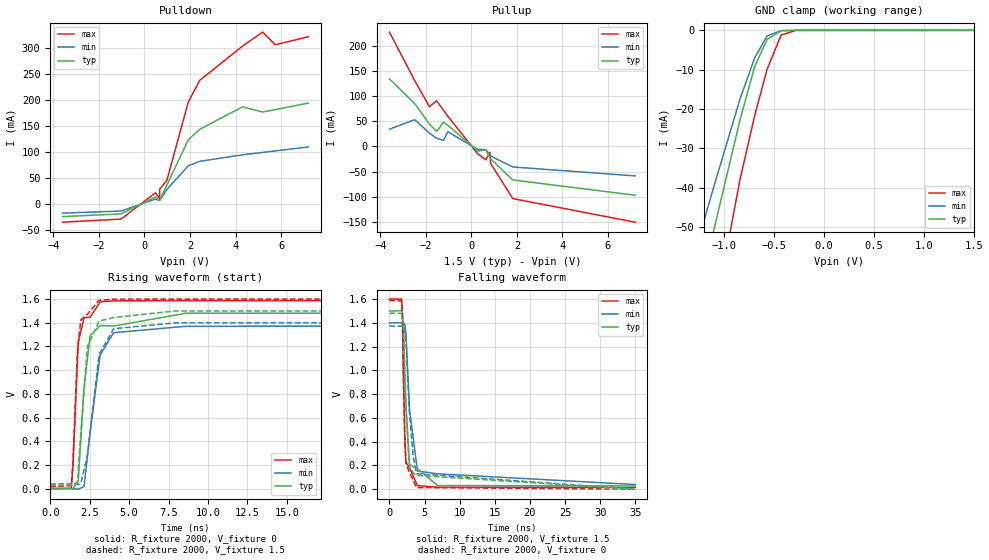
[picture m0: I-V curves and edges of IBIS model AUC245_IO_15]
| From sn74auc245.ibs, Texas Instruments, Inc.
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[Model]   AUC245_IO_15
Model_type  3-state
Enable   Active-Low
Vref =   0
Rref =   2000
Cref =   15p
Vmeas =   0.75
| variable   typ   min   max
C_comp   6.72pF   6.02pF   7.05pF
| C_pullup   6.12pF   1.56pF   13.36pF
| C_pulldown   7.55pF   6.36pF   12.72pF
| C_tri-state   6.72pF   6.02pF   7.05pF
[Temperature Range]   40   100   -40
| Ambient temperature   25   85   -40
[Voltage range]   1.5   1.4   1.6
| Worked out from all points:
|   slope of the pulldown table from 0 to 0.225 V, typ, clamps not added: 37.2 ohm
|   slope of the pullup table from 0 to 0.225 V, typ, clamps not added: 29.7 ohm
|   GND clamp passes 1 mA (typ) near -0.52 V on its own axis
|   rising waveform, R_fixture 2000, V_fixture 0: 20-80 % time 490ps typ, 711ps min, 321ps max; typ from 0 V to 1.48 V
|   falling waveform, R_fixture 2000, V_fixture 1.5: 20-80 % time 571ps typ, 892ps min, 349ps max; typ from 1.5 V to 0.027 V
|   rising waveform, R_fixture 2000, V_fixture 1.5: 20-80 % time 484ps typ, 705ps min, 319ps max; typ from 0.027 V to 1.5 V
|   falling waveform, R_fixture 2000, V_fixture 0: 20-80 % time 571ps typ, 893ps min, 348ps max; typ from 1.48 V to 0 V
[GND Clamp]
| AUC245_IO_15
|   Voltage   I(typ)   I(min)   I(max)
-3.6V     -336.3mA   -280.4mA   -411.7mA
-1.505V   -95.92mA   -76.56mA   -128.6mA
-1.37V    -80.62mA   -63.99mA   -110.1mA
-1.325V   -75.54mA   -59.84mA   -103.9mA
-1.17V    -58.19mA   -45.73mA   -82.61mA
-1.12V    -52.66mA   -41.26mA   -75.74mA
-840mV    -22.7mA    -17.42mA   -37.85mA
-695mV    -9.29mA    -7.054mA   -21.78mA
-570mV    -2.277mA   -1.41mA    -9.889mA
-430mV    -113.4uA   -63.2uA    -1.204mA
-280mV    -1.35uA    -1.745uA   -8.322uA
1.5V      582.6pA    10.38nA    575.8pA
[Pulldown]
| AUC245_IO_15
|   Voltage   I(typ)   I(min)   I(max)
-3.6V     -23.87mA   -17.26mA   -34.61mA
-1.03V    -18.71mA   -13.15mA   -28.63mA
485mV     13.68mA    9.737mA    21.72mA
660mV     8.179mA    6.945mA    10.96mA
670mV     8.318mA    7.09mA     28.79mA
985mV     36.64mA    28.23mA    45.9mA
1.925V    123.7mA    73.77mA    196.2mA
2.43V     143.9mA    82.33mA    237.9mA
4.315V    186.9mA    94.81mA    303.8mA
5.195V    177mA      99.37mA    330.5mA
5.745V    181.6mA    102.3mA    306.2mA
7.2V      194.2mA    109.9mA    321.5mA
[Pullup]
| AUC245_IO_15
|   Voltage   I(typ)   I(min)   I(max)
-3.6V     133.9mA    34.19mA    226.6mA
-2.49V    84.93mA    52.91mA    130.4mA
-1.84V    44.23mA    26.42mA    78.7mA
-1.525V   29.94mA    16.1mA     90.45mA
-1.225V   48.04mA    12.14mA    71.67mA
-1.03V    41.9mA     29.08mA    59.59mA
275mV     -9.031mA   -5.857mA   -14.38mA
640mV     -6.934mA   -6.164mA   -26.37mA
820mV     -23.64mA   -17.98mA   -11.49mA
845mV     -24.58mA   -18.83mA   -33.67mA
1.82V     -66.39mA   -40.69mA   -103.3mA
7.2V      -96.74mA   -58.4mA    -150.1mA
[Ramp]
| AUC245_IO_15
| variable   typ   min   max
dV/dt_r   0.89/4.98E-10   0.83/7.15E-10   0.96/3.28E-10
dV/dt_f   0.88/5.78E-10   0.82/8.95E-10   0.95/3.55E-10
R_load = 2000
[Rising Waveform]
| AUC245_IO_15
R_fixture =   2000
C_fixture =   0
L_fixture =   0
V_fixture =   0
V_fixture_min = 0
V_fixture_max = 0
|   Time   V(typ)   V(min)   V(max)
0s        10.33nV    38.77nV    1.328nV
1.335ns   -1.757mV   1.177mV    3.247mV
1.43ns    -3.766mV   679.3uV    174.4mV
1.775ns   66.43mV    -4.519mV   1.237V
2.14ns    851mV      16.9mV     1.442V
2.52ns    1.288V     465.3mV    1.446V
3.16ns    1.376V     1.128V     1.576V
4.01ns    1.372V     1.316V     1.585V
8.57ns    1.48V      1.37V      1.587V
34.99ns   1.481V     1.373V     1.587V
[Falling Waveform]
| AUC245_IO_15
R_fixture =   2000
C_fixture =   0
L_fixture =   0
V_fixture =   1.5
V_fixture_min = 1.4
V_fixture_max = 1.6
|   Time   V(typ)   V(min)   V(max)
0s        1.5V       1.4V       1.6V
1.725ns   1.501V     1.4V       1.6V
1.835ns   1.489V     1.401V     1.491V
1.99ns    1.376V     1.402V     967mV
2.185ns   968.9mV    1.389V     440mV
2.345ns   709.7mV    1.313V     231mV
2.855ns   207.9mV    672.2mV    178.6mV
3.99ns    171.8mV    152.8mV    29.68mV
6.845ns   30.64mV    129.2mV    16.68mV
34.99ns   27.22mV    38.79mV    16.42mV
[Rising Waveform]
| AUC245_IO_15
R_fixture =   2000
C_fixture =   0
L_fixture =   0
V_fixture =   1.5
V_fixture_min = 1.4
V_fixture_max = 1.6
|   Time   V(typ)   V(min)   V(max)
0s        27.17mV    38.75mV    16.4mV
1.335ns   25.92mV    39.85mV    24.66mV
1.435ns   24.4mV     39.42mV    218.6mV
1.72ns    56.77mV    36.94mV    1.152V
1.93ns    455.1mV    39.19mV    1.422V
2.36ns    1.2V       285.6mV    1.473V
3.09ns    1.414V     1.133V     1.589V
4.02ns    1.444V     1.35V      1.599V
7.935ns   1.5V       1.399V     1.6V
34.99ns   1.5V       1.4V       1.6V
[Falling Waveform]
| AUC245_IO_15
R_fixture =   2000
C_fixture =   0
L_fixture =   0
V_fixture =   0
V_fixture_min = 0
V_fixture_max = 0
|   Time   V(typ)   V(min)   V(max)
0s        1.481V     1.373V     1.587V
1.725ns   1.479V     1.371V     1.585V
1.835ns   1.465V     1.371V     1.474V
1.985ns   1.353V     1.37V      965.6mV
2.18ns    956.7mV    1.353V     431.5mV
2.34ns    694.3mV    1.274V     217.8mV
2.825ns   192.7mV    660.7mV    144.7mV
3.385ns   136.8mV    270.5mV    73.23mV
3.885ns   116.2mV    129.1mV    13.36mV
34.99ns   49.19uV    40.58uV    16.48uV
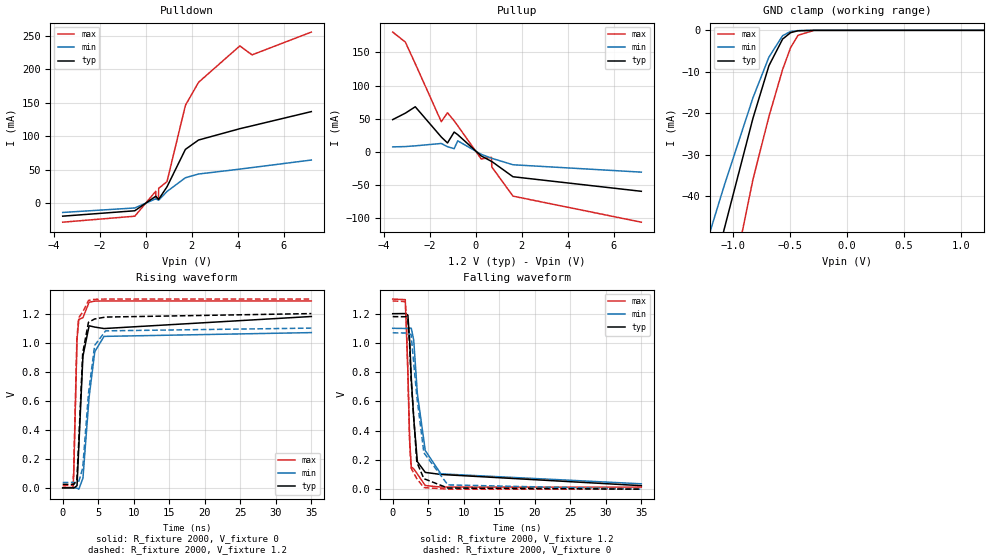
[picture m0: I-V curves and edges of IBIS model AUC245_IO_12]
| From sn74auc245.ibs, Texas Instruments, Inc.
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[Model]   AUC245_IO_12
Model_type  3-state
Enable   Active-Low
Vref =   0
Rref =   2000
Cref =   15p
Vmeas =   0.6
| variable   typ   min   max
C_comp   6.81pF   6.18pF   7.14pF
| C_pullup   5.84pF   0.07pF   10.81pF
| C_pulldown   7.37pF   6.51pF   8.47pF
| C_tri-state   6.81pF   6.18pF   7.14pF
[Temperature Range]   40   100   -40
| Ambient temperature   25   85   -40
[Voltage range]   1.2   1.1   1.3
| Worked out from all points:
|   slope of the pulldown table from 0 to 0.18 V, typ, clamps not added: 42.1 ohm
|   slope of the pullup table from 0 to 0.18 V, typ, clamps not added: 38.3 ohm
|   GND clamp passes 1 mA (typ) near -0.52 V on its own axis
|   rising waveform, R_fixture 2000, V_fixture 0: 20-80 % time 675ps typ, 1.11ns min, 403ps max; typ from 0 V to 1.18 V
|   falling waveform, R_fixture 2000, V_fixture 1.2: 20-80 % time 875ps typ, 1.51ns min, 437ps max; typ from 1.2 V to 0.024 V
|   rising waveform, R_fixture 2000, V_fixture 1.2: 20-80 % time 667ps typ, 1.11ns min, 397ps max; typ from 0.024 V to 1.2 V
|   falling waveform, R_fixture 2000, V_fixture 0: 20-80 % time 868ps typ, 1.46ns min, 432ps max; typ from 1.18 V to 0 V
[GND Clamp]
| AUC245_IO_12
|   Voltage   I(typ)   I(min)   I(max)
-3.6V     -336.3mA   -280.4mA   -411.7mA
-1.455V   -90.24mA   -71.88mA   -121.7mA
-1.28V    -70.48mA   -55.71mA   -97.73mA
-1.115V   -52.1mA    -40.81mA   -75.05mA
-1.075V   -47.7mA    -37.27mA   -69.56mA
-825mV    -21.19mA   -16.25mA   -35.96mA
-685mV    -8.523mA   -6.452mA   -20.79mA
-565mV    -2.109mA   -1.285mA   -9.456mA
-495mV    -562.2uA   -286.3uA   -4.171mA
-430mV    -113.4uA   -63.2uA    -1.204mA
-290mV    -1.822uA   -2.294uA   -12.44uA
1.2V      468.4pA    10.26nA    412.7pA
[Pulldown]
| AUC245_IO_12
|   Voltage   I(typ)   I(min)   I(max)
-3.6V     -19.18mA   -13.63mA   -28.17mA
-470mV    -11.13mA   -6.91mA    -19.23mA
440mV     10.48mA    6.706mA    17.92mA
445mV     10.59mA    6.769mA    6.318mA
560mV     5.857mA    4.698mA    8.209mA
570mV     5.97mA     4.785mA    22.41mA
930mV     24.61mA    17.66mA    32.37mA
1.73V     80.53mA    38.18mA    146.2mA
2.3V      94.46mA    43.74mA    180.6mA
4.095V    111.4mA    51.05mA    235mA
4.625V    115.7mA    53.39mA    221.6mA
7.2V      136.9mA    64.6mA     255.6mA
[Pullup]
| AUC245_IO_12
|   Voltage   I(typ)   I(min)   I(max)
-3.6V     48.8mA     7.73mA     180.5mA
-3.05V    58.5mA     8.2mA      165.4mA
-2.62V    68.11mA    9.305mA    132.9mA
-1.49V    22.6mA     12.87mA    45.69mA
-1.22V    13.65mA    7.955mA    59.11mA
-930mV    30.05mA    5.089mA    46.94mA
-775mV    26.1mA     16.83mA    39.5mA
245mV     -5.916mA   -3.381mA   -10.43mA
690mV     -14.05mA   -9.318mA   -7.997mA
705mV     -14.25mA   -9.471mA   -22.45mA
1.625V    -37.2mA    -19.16mA   -66.38mA
7.2V      -59.1mA    -30.27mA   -105.6mA
[Ramp]
| AUC245_IO_12
| variable   typ   min   max
dV/dt_r   0.71/6.80E-10   0.65/1.12E-09   0.78/4.08E-10
dV/dt_f   0.71/8.78E-10   0.64/1.51E-09   0.77/4.46E-10
R_load = 2000
[Rising Waveform]
| AUC245_IO_12
R_fixture =   2000
C_fixture =   0
L_fixture =   0
V_fixture =   0
V_fixture_min = 0
V_fixture_max = 0
|   Time   V(typ)   V(min)   V(max)
0s        9.669nV    41.18nV    1.053nV
1.455ns   -488.4uV   1.554mV    3.9mV
1.55ns    -1.633mV   1.348mV    95.36mV
2.015ns   15.19mV    -2.355mV   1.024V
2.27ns    288mV      -9.057mV   1.16V
2.845ns   906.3mV    66.07mV    1.172V
3.715ns   1.116V     624.5mV    1.278V
4.515ns   1.107V     937.8mV    1.286V
5.815ns   1.097V     1.043V     1.287V
34.99ns   1.18V      1.069V     1.287V
[Falling Waveform]
| AUC245_IO_12
R_fixture =   2000
C_fixture =   0
L_fixture =   0
V_fixture =   1.2
V_fixture_min = 1.1
V_fixture_max = 1.3
|   Time   V(typ)   V(min)   V(max)
0s        1.2V       1.1V       1.3V
1.765ns   1.201V     1.099V     1.296V
2.135ns   1.19V      1.1V       807.9mV
2.385ns   1.016V     1.102V     335.6mV
2.615ns   759.1mV    1.1V       151.3mV
2.955ns   486.2mV    1.02V      139.4mV
3.47ns    188.1mV    653.9mV    104mV
4.58ns    114.6mV    264mV      24.77mV
6.78ns    100.6mV    104.7mV    14.27mV
34.99ns   24.03mV    36.66mV    13.88mV
[Rising Waveform]
| AUC245_IO_12
R_fixture =   2000
C_fixture =   0
L_fixture =   0
V_fixture =   1.2
V_fixture_min = 1.1
V_fixture_max = 1.3
|   Time   V(typ)   V(min)   V(max)
0s        23.98mV    36.61mV    13.86mV
1.445ns   23.79mV    37.8mV     18.72mV
1.55ns    22.98mV    37.6mV     122.9mV
1.99ns    53.17mV    36.37mV    1.022V
2.235ns   294.8mV    39.47mV    1.171V
2.815ns   928mV      136.6mV    1.21V
3.625ns   1.14V      648.3mV    1.291V
4.495ns   1.163V     981.1mV    1.298V
6.03ns    1.176V     1.081V     1.3V
34.99ns   1.2V       1.1V       1.3V
[Falling Waveform]
| AUC245_IO_12
R_fixture =   2000
C_fixture =   0
L_fixture =   0
V_fixture =   0
V_fixture_min = 0
V_fixture_max = 0
|   Time   V(typ)   V(min)   V(max)
0s        1.18V      1.069V     1.287V
1.755ns   1.179V     1.068V     1.283V
1.915ns   1.178V     1.067V     1.174V
2.13ns    1.162V     1.066V     798.5mV
2.375ns   990.4mV    1.062V     327mV
2.59ns    748.7mV    1.055V     143.8mV
3.395ns   184.2mV    632.6mV    71.57mV
4.385ns   71.83mV    249mV      10.84mV
7.76ns    7.669mV    29.21mV    214.4uV
34.99ns   52.44uV    38.88uV    18.91uV
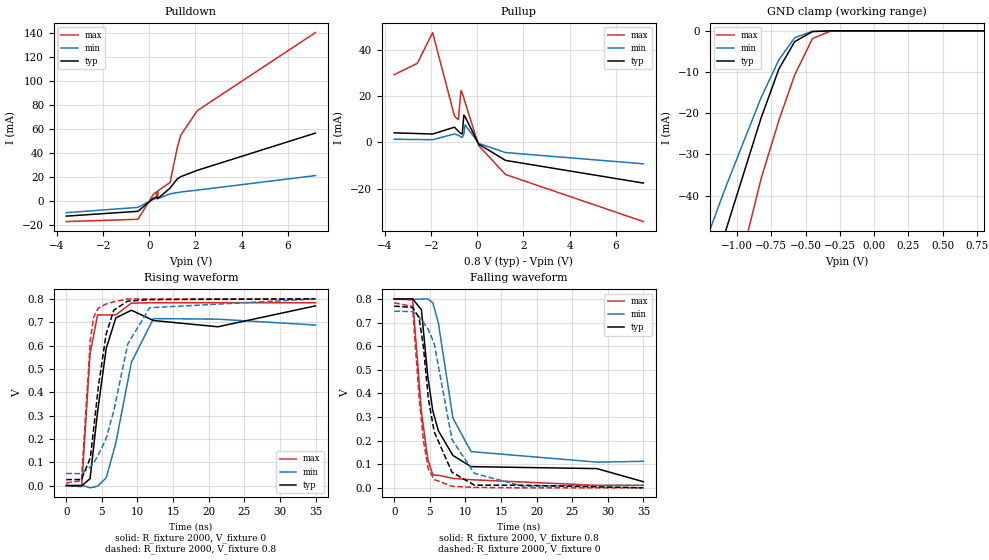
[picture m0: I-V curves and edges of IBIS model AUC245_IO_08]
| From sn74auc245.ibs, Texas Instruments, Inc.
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[Model]   AUC245_IO_08
Model_type  3-state
Enable   Active-Low
Vref =   0
Rref =   2000
Cref =   15p
Vmeas =   0.4
| variable   typ   min   max
C_comp   6.87pF   6.31pF   7.17pF
| C_pullup   7.04pF   2.58pF   9.50pF
| C_pulldown   7.48pF   6.83pF   7.85pF
| C_tri-state   6.87pF   6.31pF   7.17pF
[Temperature Range]   40   100   -40
| Ambient temperature   25   85   -40
[Voltage range]   0.8   0.8   0.8
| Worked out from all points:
|   slope of the pulldown table from 0 to 0.12 V, typ, clamps not added: 77.5 ohm
|   slope of the pullup table from 0 to 0.12 V, typ, clamps not added: 92.9 ohm
|   GND clamp passes 1 mA (typ) near -0.52 V on its own axis
|   rising waveform, R_fixture 2000, V_fixture 0: 20-80 % time 1.94ns typ, 2.67ns min, 1.05ns max; typ from 0 V to 0.77 V
|   falling waveform, R_fixture 2000, V_fixture 0.8: 20-80 % time 2.98ns typ, 2.31ns min, 1.49ns max; typ from 0.8 V to 0.026 V
|   rising waveform, R_fixture 2000, V_fixture 0.8: 20-80 % time 1.94ns typ, 3.6ns min, 998ps max; typ from 0.025 V to 0.8 V
|   falling waveform, R_fixture 2000, V_fixture 0: 20-80 % time 2.45ns typ, 2.95ns min, 1.37ns max; typ from 0.77 V to 0 V
[GND Clamp]
| AUC245_IO_08
|   Voltage   I(typ)   I(min)   I(max)
-3.6V     -336.3mA   -280.4mA   -411.7mA
-1.495V   -94.78mA   -75.62mA   -127.2mA
-1.45V    -89.67mA   -71.42mA   -121.1mA
-1.32V    -74.98mA   -59.38mA   -103.2mA
-1.115V   -52.1mA    -40.81mA   -75.05mA
-1.08V    -48.25mA   -37.71mA   -70.25mA
-825mV    -21.19mA   -16.25mA   -35.96mA
-695mV    -9.29mA    -7.054mA   -21.78mA
-580mV    -2.638mA   -1.685mA   -10.77mA
-450mV    -191.3uA   -100.1uA   -1.878mA
-315mV    -3.912uA   -4.445uA   -32.85uA
800mV     338.4pA    609.2pA    260.4pA
[Pulldown]
| AUC245_IO_08
|   Voltage   I(typ)   I(min)   I(max)
-3.6V     -12.84mA   -9.953mA   -17.38mA
-495mV    -8.803mA   -5.523mA   -15.47mA
175mV     2.059mA    1.185mA    5.31mA
310mV     3.174mA    2.053mA    7.502mA
315mV     3.217mA    2.087mA    2.47mA
365mV     1.856mA    1.796mA    2.807mA
370mV     1.894mA    1.829mA    8.27mA
900mV     10.66mA    5.825mA    15.37mA
1.215V    18.37mA    6.848mA    44.91mA
1.37V     20.23mA    7.332mA    55.15mA
2.09V     25.55mA    8.946mA    75.56mA
7.2V      56.63mA    21.09mA    140.7mA
[Pullup]
| AUC245_IO_08
|   Voltage   I(typ)   I(min)   I(max)
-3.6V     4.13mA     1.333mA    29.34mA
-2.595V   3.829mA    1.231mA    34.24mA
-1.935V   3.609mA    1.155mA    47.57mA
-985mV    6.593mA    3.652mA    11.35mA
-820mV    4.807mA    3.079mA    9.795mA
-705mV    3.788mA    2.41mA     22.46mA
-650mV    3.702mA    2.149mA    21.3mA
-580mV    11.83mA    3.56mA     19.16mA
-530mV    11.15mA    7.583mA    17.47mA
65mV      -779.5uA   -459.6uA   -1.427mA
1.225V    -7.819mA   -4.418mA   -13.93mA
7.2V      -17.63mA   -9.285mA   -34.31mA
[Ramp]
| AUC245_IO_08
| variable   typ   min   max
dV/dt_r   0.47/1.95E-09   0.46/3.16E-09   0.48/1.06E-09
dV/dt_f   0.46/2.98E-09   0.42/2.34E-09   0.48/1.49E-09
R_load = 2000
[Rising Waveform]
| AUC245_IO_08
R_fixture =   2000
C_fixture =   0
L_fixture =   0
V_fixture =   0
V_fixture_min = 0
V_fixture_max = 0
|   Time   V(typ)   V(min)   V(max)
0s        11.88nV    67.28nV    779.4pV
2.16ns    -1.2mV     1.612mV    -4.737mV
3.34ns    29.59mV    -9.871mV   564.9mV
4.4ns     317.4mV    -2.68mV    731.7mV
5.605ns   587.3mV    32.83mV    731mV
6.95ns    718.1mV    181.1mV    731.1mV
9.145ns   751.3mV    528.4mV    781.9mV
12.24ns   707.2mV    715.5mV    783.4mV
21.29ns   680.4mV    712.9mV    783.7mV
34.99ns   769.9mV    687.8mV    783.7mV
[Falling Waveform]
| AUC245_IO_08
R_fixture =   2000
C_fixture =   0
L_fixture =   0
V_fixture =   0.8
V_fixture_min = 0.8
V_fixture_max = 0.8
|   Time   V(typ)   V(min)   V(max)
0s        800mV      800mV      800mV
2.6ns     800.7mV    798.8mV    796.4mV
3.825ns   754.4mV    799.7mV    322.1mV
4.71ns    472.8mV    800.6mV    122.8mV
5.425ns   325.8mV    784.3mV    54.21mV
6.205ns   241.6mV    698.3mV    53.42mV
8.245ns   137.3mV    295.8mV    40.22mV
10.79ns   89.95mV    153.6mV    34.6mV
28.47ns   81.57mV    109mV      10.65mV
34.99ns   26.03mV    112.4mV    10.64mV
[Rising Waveform]
| AUC245_IO_08
R_fixture =   2000
C_fixture =   0
L_fixture =   0
V_fixture =   0.8
V_fixture_min = 0.8
V_fixture_max = 0.8
|   Time   V(typ)   V(min)   V(max)
0s        25.46mV    51.93mV    10.6mV
2.13ns    26.07mV    50.98mV    21.22mV
3.375ns   118.7mV    80.02mV    620.9mV
3.85ns    244.7mV    96.19mV    722.4mV
4.515ns   426mV      132.5mV    760.5mV
5.59ns    648.1mV    201.2mV    778.1mV
6.675ns   751.8mV    320.6mV    787.7mV
8.63ns    790.6mV    606.3mV    799.7mV
11.7ns    796.8mV    761.9mV    799.7mV
34.99ns   799.9mV    799.7mV    800mV
[Falling Waveform]
| AUC245_IO_08
R_fixture =   2000
C_fixture =   0
L_fixture =   0
V_fixture =   0
V_fixture_min = 0
V_fixture_max = 0
|   Time   V(typ)   V(min)   V(max)
0s        770mV      748.6mV    783.8mV
2.575ns   764.1mV    746.7mV    768.9mV
3.485ns   722mV      724mV      387.1mV
4.105ns   596.6mV    701.5mV    201mV
4.79ns    378.5mV    670.6mV    80.67mV
5.62ns    237.3mV    611.5mV    35.26mV
8.115ns   66.1mV     204.6mV    6.75mV
11.25ns   11.54mV    61.35mV    1.852mV
18.01ns   10.99mV    7.534mV    100.4uV
34.99ns   135.4uV    11.18mV    37.88uV
